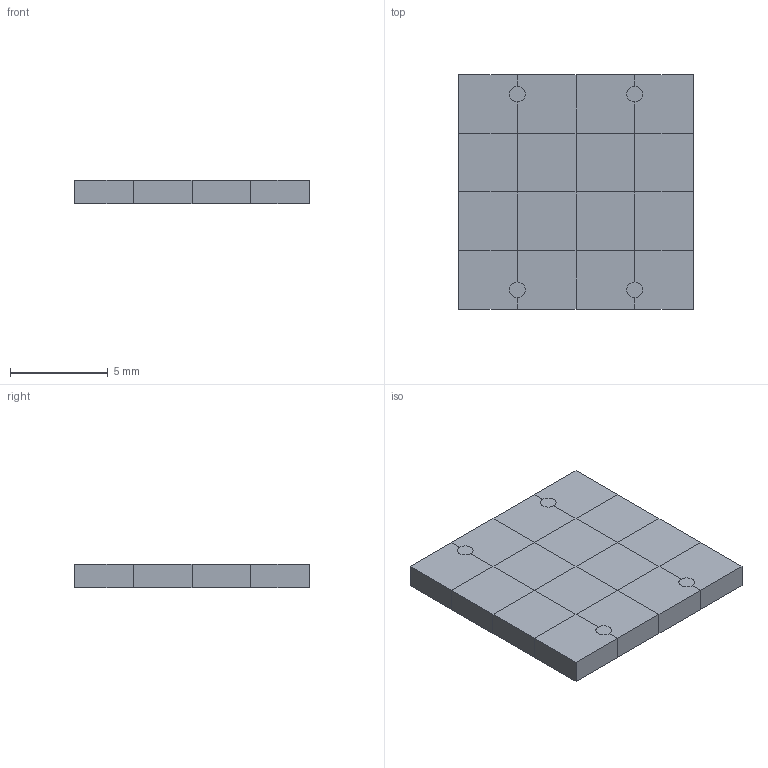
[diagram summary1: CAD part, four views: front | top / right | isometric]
STEP (ISO 10303-21) file: header records copied from the file, then geometry measured from it (millimetres).
FILE_DESCRIPTION(('Open CASCADE Model'),'2;1');
FILE_NAME('Open CASCADE Shape Model','2026-11-20T12:56:51',('Author'),( 'Open CASCADE'),'Open CASCADE STEP processor 7.9','Open CASCADE 7.9' ,'Unknown');
FILE_SCHEMA(('AUTOMOTIVE_DESIGN { 1 0 10303 214 1 1 1 1 }'));
Length unit declared in the file: millimetre
Products named in the file (3): manifold_AD_33-34_3; fluid; solid
Assembly tree (2 placements, depth 2):
  manifold_AD_33-34_3
    fluid
    solid
Bounding box: 12 x 12 x 1.2 mm (x, y, z)
Volume: 172.8 mm3; surface area: 1393.2 mm2
Topology: 2 solids, 2 shells, 1212 faces, 4308 edges, 2426 vertices
Faces by surface type: plane 1204, cylinder 8
Full cylindrical faces by diameter (mm): 0.8 x8
Entity records: 100942 total; most frequent: CARTESIAN_POINT 16613, DIRECTION 15370, LINE 12876, VECTOR 12876, ORIENTED_EDGE 8616, PCURVE 8616, DEFINITIONAL_REPRESENTATION 8616, EDGE_CURVE 4308
One B-rep face of a CAD part: STEP entity #53898.
In plain terms, the planar face has unit normal (0, 0, 1).
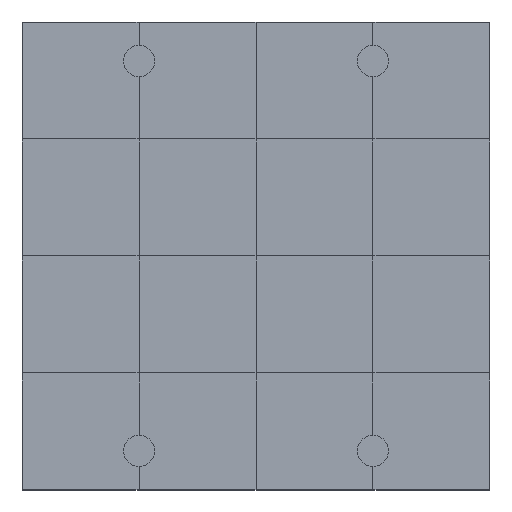
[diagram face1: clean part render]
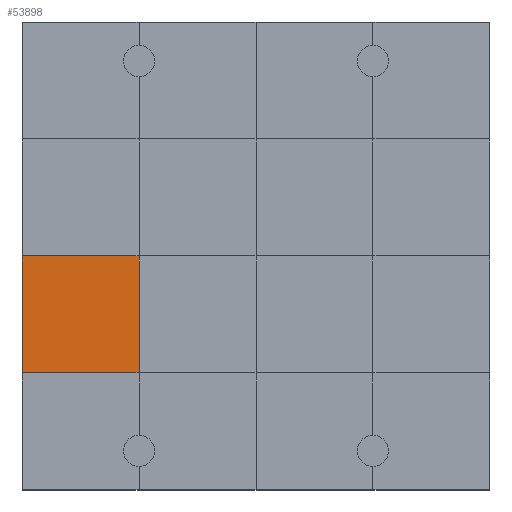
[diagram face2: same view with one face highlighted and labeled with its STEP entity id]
Its self-contained STEP definition (entity closure, numbers rounded to 3 decimals):
#53448 = VERTEX_POINT('',#53449);
#53449 = CARTESIAN_POINT('',(0.,3.,1.2));
#53463 = PLANE('',#53464);
#53464 = AXIS2_PLACEMENT_3D('',#53465,#53466,#53467);
#53465 = CARTESIAN_POINT('',(0.,3.,0.));
#53466 = DIRECTION('',(1.,0.,-0.));
#53467 = DIRECTION('',(0.,0.,1.));
#53489 = PLANE('',#53490);
#53490 = AXIS2_PLACEMENT_3D('',#53491,#53492,#53493);
#53491 = CARTESIAN_POINT('',(0.,0.,1.2));
#53492 = DIRECTION('',(0.,0.,1.));
#53493 = DIRECTION('',(1.,0.,-0.));
#53640 = VERTEX_POINT('',#53641);
#53641 = CARTESIAN_POINT('',(3.,3.,1.2));
#53662 = EDGE_CURVE('',#53448,#53640,#53663,.T.);
#53663 = SURFACE_CURVE('',#53664,(#53668,#53675),.PCURVE_S1.);
#53664 = LINE('',#53665,#53666);
#53665 = CARTESIAN_POINT('',(0.,3.,1.2));
#53666 = VECTOR('',#53667,1.);
#53667 = DIRECTION('',(1.,0.,-0.));
#53668 = PCURVE('',#53489,#53669);
#53669 = DEFINITIONAL_REPRESENTATION('',(#53670),#53674);
#53670 = LINE('',#53671,#53672);
#53671 = CARTESIAN_POINT('',(0.,3.));
#53672 = VECTOR('',#53673,1.);
#53673 = DIRECTION('',(1.,0.));
#53674 = ( GEOMETRIC_REPRESENTATION_CONTEXT(2) 
PARAMETRIC_REPRESENTATION_CONTEXT() REPRESENTATION_CONTEXT('2D SPACE',''
  ) );
#53675 = PCURVE('',#53676,#53681);
#53676 = PLANE('',#53677);
#53677 = AXIS2_PLACEMENT_3D('',#53678,#53679,#53680);
#53678 = CARTESIAN_POINT('',(0.,3.,1.2));
#53679 = DIRECTION('',(0.,0.,1.));
#53680 = DIRECTION('',(1.,0.,-0.));
#53681 = DEFINITIONAL_REPRESENTATION('',(#53682),#53686);
#53682 = LINE('',#53683,#53684);
#53683 = CARTESIAN_POINT('',(0.,0.));
#53684 = VECTOR('',#53685,1.);
#53685 = DIRECTION('',(1.,0.));
#53686 = ( GEOMETRIC_REPRESENTATION_CONTEXT(2) 
PARAMETRIC_REPRESENTATION_CONTEXT() REPRESENTATION_CONTEXT('2D SPACE',''
  ) );
#53721 = VERTEX_POINT('',#53722);
#53722 = CARTESIAN_POINT('',(0.,6.,1.2));
#53748 = EDGE_CURVE('',#53448,#53721,#53749,.T.);
#53749 = SURFACE_CURVE('',#53750,(#53754,#53761),.PCURVE_S1.);
#53750 = LINE('',#53751,#53752);
#53751 = CARTESIAN_POINT('',(0.,3.,1.2));
#53752 = VECTOR('',#53753,1.);
#53753 = DIRECTION('',(-0.,1.,0.));
#53754 = PCURVE('',#53463,#53755);
#53755 = DEFINITIONAL_REPRESENTATION('',(#53756),#53760);
#53756 = LINE('',#53757,#53758);
#53757 = CARTESIAN_POINT('',(1.2,0.));
#53758 = VECTOR('',#53759,1.);
#53759 = DIRECTION('',(0.,-1.));
#53760 = ( GEOMETRIC_REPRESENTATION_CONTEXT(2) 
PARAMETRIC_REPRESENTATION_CONTEXT() REPRESENTATION_CONTEXT('2D SPACE',''
  ) );
#53761 = PCURVE('',#53676,#53762);
#53762 = DEFINITIONAL_REPRESENTATION('',(#53763),#53767);
#53763 = LINE('',#53764,#53765);
#53764 = CARTESIAN_POINT('',(0.,0.));
#53765 = VECTOR('',#53766,1.);
#53766 = DIRECTION('',(0.,1.));
#53767 = ( GEOMETRIC_REPRESENTATION_CONTEXT(2) 
PARAMETRIC_REPRESENTATION_CONTEXT() REPRESENTATION_CONTEXT('2D SPACE',''
  ) );
#53898 = ADVANCED_FACE('',(#53899),#53676,.T.);
#53899 = FACE_BOUND('',#53900,.T.);
#53900 = EDGE_LOOP('',(#53901,#53902,#53903,#53931));
#53901 = ORIENTED_EDGE('',*,*,#53748,.F.);
#53902 = ORIENTED_EDGE('',*,*,#53662,.T.);
#53903 = ORIENTED_EDGE('',*,*,#53904,.T.);
#53904 = EDGE_CURVE('',#53640,#53905,#53907,.T.);
#53905 = VERTEX_POINT('',#53906);
#53906 = CARTESIAN_POINT('',(3.,6.,1.2));
#53907 = SURFACE_CURVE('',#53908,(#53912,#53919),.PCURVE_S1.);
#53908 = LINE('',#53909,#53910);
#53909 = CARTESIAN_POINT('',(3.,3.,1.2));
#53910 = VECTOR('',#53911,1.);
#53911 = DIRECTION('',(-0.,1.,0.));
#53912 = PCURVE('',#53676,#53913);
#53913 = DEFINITIONAL_REPRESENTATION('',(#53914),#53918);
#53914 = LINE('',#53915,#53916);
#53915 = CARTESIAN_POINT('',(3.,0.));
#53916 = VECTOR('',#53917,1.);
#53917 = DIRECTION('',(0.,1.));
#53918 = ( GEOMETRIC_REPRESENTATION_CONTEXT(2) 
PARAMETRIC_REPRESENTATION_CONTEXT() REPRESENTATION_CONTEXT('2D SPACE',''
  ) );
#53919 = PCURVE('',#53920,#53925);
#53920 = PLANE('',#53921);
#53921 = AXIS2_PLACEMENT_3D('',#53922,#53923,#53924);
#53922 = CARTESIAN_POINT('',(3.,3.,1.2));
#53923 = DIRECTION('',(0.,0.,1.));
#53924 = DIRECTION('',(1.,0.,-0.));
#53925 = DEFINITIONAL_REPRESENTATION('',(#53926),#53930);
#53926 = LINE('',#53927,#53928);
#53927 = CARTESIAN_POINT('',(0.,0.));
#53928 = VECTOR('',#53929,1.);
#53929 = DIRECTION('',(0.,1.));
#53930 = ( GEOMETRIC_REPRESENTATION_CONTEXT(2) 
PARAMETRIC_REPRESENTATION_CONTEXT() REPRESENTATION_CONTEXT('2D SPACE',''
  ) );
#53931 = ORIENTED_EDGE('',*,*,#53932,.F.);
#53932 = EDGE_CURVE('',#53721,#53905,#53933,.T.);
#53933 = SURFACE_CURVE('',#53934,(#53938,#53945),.PCURVE_S1.);
#53934 = LINE('',#53935,#53936);
#53935 = CARTESIAN_POINT('',(0.,6.,1.2));
#53936 = VECTOR('',#53937,1.);
#53937 = DIRECTION('',(1.,0.,-0.));
#53938 = PCURVE('',#53676,#53939);
#53939 = DEFINITIONAL_REPRESENTATION('',(#53940),#53944);
#53940 = LINE('',#53941,#53942);
#53941 = CARTESIAN_POINT('',(0.,3.));
#53942 = VECTOR('',#53943,1.);
#53943 = DIRECTION('',(1.,0.));
#53944 = ( GEOMETRIC_REPRESENTATION_CONTEXT(2) 
PARAMETRIC_REPRESENTATION_CONTEXT() REPRESENTATION_CONTEXT('2D SPACE',''
  ) );
#53945 = PCURVE('',#53946,#53951);
#53946 = PLANE('',#53947);
#53947 = AXIS2_PLACEMENT_3D('',#53948,#53949,#53950);
#53948 = CARTESIAN_POINT('',(0.,6.,1.2));
#53949 = DIRECTION('',(0.,0.,1.));
#53950 = DIRECTION('',(1.,0.,-0.));
#53951 = DEFINITIONAL_REPRESENTATION('',(#53952),#53956);
#53952 = LINE('',#53953,#53954);
#53953 = CARTESIAN_POINT('',(0.,0.));
#53954 = VECTOR('',#53955,1.);
#53955 = DIRECTION('',(1.,0.));
#53956 = ( GEOMETRIC_REPRESENTATION_CONTEXT(2) 
PARAMETRIC_REPRESENTATION_CONTEXT() REPRESENTATION_CONTEXT('2D SPACE',''
  ) );
